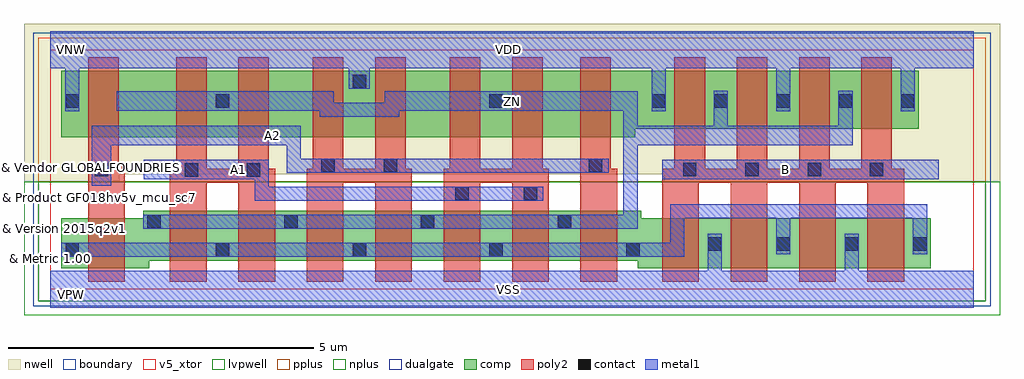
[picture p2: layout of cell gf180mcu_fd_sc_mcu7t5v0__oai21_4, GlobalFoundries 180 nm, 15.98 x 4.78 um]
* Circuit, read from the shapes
.subckt gf180mcu_fd_sc_mcu7t5v0__oai21_4 A1 A2 B VDD VNW VSS ZN
XM1 ZN A2 n1 VSUBS nfet_05v0 w=0.82u l=0.6u m=4
XM2 n1 A1 ZN VSUBS nfet_05v0 w=0.82u l=0.6u m=4
XM3 VSS B n1 VSUBS nfet_05v0 w=0.82u l=0.6u m=4
XM4 n2 A2 VDD VNW pfet_05v0 w=1.095u l=0.5u
XM5 ZN A1 n2 VNW pfet_05v0 w=1.095u l=0.5u
XM6 n3 A1 ZN VNW pfet_05v0 w=1.095u l=0.5u
XM7 VDD A2 n3 VNW pfet_05v0 w=1.095u l=0.5u
XM8 n4 A2 VDD VNW pfet_05v0 w=1.095u l=0.5u
XM9 ZN A1 n4 VNW pfet_05v0 w=1.095u l=0.5u
XM10 n5 A1 ZN VNW pfet_05v0 w=1.095u l=0.5u
XM11 VDD A2 n5 VNW pfet_05v0 w=1.095u l=0.5u
XM12 ZN B VDD VNW pfet_05v0 w=0.955u l=0.5u m=4
.ends

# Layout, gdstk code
import gdstk
lib = gdstk.Library(unit=1e-6, precision=1e-09)
def R(c, l, rs):  # rectangles x0, y0, x1, y1
    for r in rs: c.add(gdstk.rectangle(r[:2], r[2:], *l))
def A(c, l, x, y, w, h, nx, ny, dx, dy):  # array of equal rectangles
    R(c, l, [(x+i*dx, y+j*dy, x+i*dx+w, y+j*dy+h) for i in range(nx) for j in range(ny)])
def P(c, l, *ps):  # polygons
    for p in ps: c.add(gdstk.Polygon(p, *l))
boundary = (0, 0)
nwell = (21, 0)
comp = (22, 0)
poly2 = (30, 0)
pplus = (31, 0)
nplus = (32, 0)
contact = (33, 0)
metal1 = (34, 0)
dualgate = (55, 0)
v5_xtor = (112, 1)
lvpwell = (204, 0)

gf180mcu_fd_sc_mcu7t5v0_ = lib.new_cell('gf180mcu_fd_sc_mcu7t5v0__oai21_4')
R(gf180mcu_fd_sc_mcu7t5v0_, boundary, [(0,0,15.12,3.92)])
P(gf180mcu_fd_sc_mcu7t5v0_, nwell, [(-0.43,1.76),(-0.43,4.35),(15.55,4.35),(15.55,1.76),(10.055,1.76),(10.055,1.885),(1.14,1.885),(1.14,1.76)])
P(gf180mcu_fd_sc_mcu7t5v0_, comp, [(0.18,2.485),(0.18,3.58),(14.22,3.58),(14.22,2.625),(9.58,2.625),(9.58,2.485)],
  [(0.18,0.34),(0.18,1.16),(1.52,1.16),(1.52,1.285),(9.68,1.285),(9.68,1.16),(14.42,1.16),(14.42,0.34),(9.62,0.34),(9.62,0.465),(1.62,0.465),(1.62,0.34)])
P(gf180mcu_fd_sc_mcu7t5v0_, poly2, [(0.62,0.12),(0.62,3.8),(1.12,3.8),(1.12,2.04),(1.22,2.04),(1.22,0.12)],
  [(1.96,0.12),(1.96,1.97),(2.06,1.97),(2.06,3.8),(2.56,3.8),(2.56,1.97),(3.08,1.97),(3.08,3.8),(3.58,3.8),(3.58,1.97),(3.68,1.97),(3.68,0.12),(3.08,0.12),(3.08,1.74),(2.56,1.74),(2.56,0.12)],
  [(4.2,0.12),(4.2,1.97),(4.3,1.97),(4.3,3.8),(4.8,3.8),(4.8,1.97),(5.32,1.97),(5.32,3.8),(5.82,3.8),(5.82,1.97),(5.92,1.97),(5.92,0.12),(5.32,0.12),(5.32,1.74),(4.8,1.74),(4.8,0.12)],
  [(6.44,0.12),(6.44,1.97),(6.54,1.97),(6.54,3.8),(7.04,3.8),(7.04,1.97),(7.56,1.97),(7.56,3.8),(8.06,3.8),(8.06,1.97),(8.16,1.97),(8.16,0.12),(7.56,0.12),(7.56,1.74),(7.04,1.74),(7.04,0.12)],
  [(8.68,0.12),(8.68,3.8),(9.18,3.8),(9.18,1.97),(9.28,1.97),(9.28,0.12)],
  [(10.02,0.12),(10.02,1.97),(10.22,1.97),(10.22,3.8),(10.72,3.8),(10.72,1.97),(11.24,1.97),(11.24,3.8),(11.74,3.8),(11.74,1.97),(12.26,1.97),(12.26,3.8),(12.76,3.8),(12.76,1.97),(13.28,1.97),(13.28,3.8),(13.78,3.8),(13.78,1.97),(13.98,1.97),(13.98,0.12),(13.38,0.12),(13.38,1.74),(12.86,1.74),(12.86,0.12),(12.26,0.12),(12.26,1.74),(11.74,1.74),(11.74,0.12),(11.14,0.12),(11.14,1.74),(10.62,1.74),(10.62,0.12)])
R(gf180mcu_fd_sc_mcu7t5v0_, pplus, [(-0.2,1.76,15.32,4.12)])
R(gf180mcu_fd_sc_mcu7t5v0_, nplus, [(-0.2,-0.2,15.32,1.76)])
A(gf180mcu_fd_sc_mcu7t5v0_, contact, 2.71, 0.535, 0.22, 0.22, 4, 1, 2.24, 0)
A(gf180mcu_fd_sc_mcu7t5v0_, contact, 10.77, 0.63, 0.22, 0.22, 4, 1, 1.12, 0)
A(gf180mcu_fd_sc_mcu7t5v0_, contact, 1.59, 0.995, 0.22, 0.22, 4, 1, 2.24, 0)
A(gf180mcu_fd_sc_mcu7t5v0_, contact, 10.36, 1.85, 0.22, 0.22, 4, 1, 1.02, 0)
A(gf180mcu_fd_sc_mcu7t5v0_, contact, 9.85, 2.97, 0.22, 0.22, 5, 1, 1.02, 0)
R(gf180mcu_fd_sc_mcu7t5v0_, contact, [(0.25,0.535,0.47,0.755), (6.63,1.455,6.85,1.675), (7.75,1.455,7.97,1.675), (2.2,1.845,2.42,2.065), (3.22,1.845,3.44,2.065), (0.73,1.85,0.95,2.07), (4.44,1.915,4.66,2.135), (5.46,1.915,5.68,2.135), (8.82,1.915,9.04,2.135), (0.25,2.97,0.47,3.19), (2.71,2.97,2.93,3.19), (7.19,2.97,7.41,3.19), (4.95,3.29,5.17,3.51)])
R(gf180mcu_fd_sc_mcu7t5v0_, metal1, [(10.02,1.8,14.55,2.12)])
P(gf180mcu_fd_sc_mcu7t5v0_, metal1, [(3.35,1.45),(3.35,1.8),(1.53,1.8),(1.53,2.12),(3.58,2.12),(3.58,1.68),(8.07,1.68),(8.07,1.45)],
  [(0.68,1.695),(0.68,2.68),(4.1,2.68),(4.1,2.14),(9.14,2.14),(9.14,1.91),(3.87,1.91),(3.87,2.36),(1,2.36),(1,1.695)],
  [(1.52,0.99),(1.52,1.22),(9.385,1.22),(9.385,2.92),(5.71,2.92),(5.71,2.825),(4.41,2.825),(4.41,2.92),(1.085,2.92),(1.085,3.24),(4.64,3.24),(4.64,3.055),(5.48,3.055),(5.48,3.24),(9.615,3.24),(9.615,2.68),(10.865,2.68),(10.865,3.25),(11.095,3.25),(11.095,2.68),(12.905,2.68),(12.905,3.25),(13.135,3.25),(13.135,2.36),(9.615,2.36),(9.615,0.99)],
  [(0.18,0.53),(0.18,0.76),(10.15,0.76),(10.15,1.39),(14.355,1.39),(14.355,0.57),(14.125,0.57),(14.125,1.16),(12.115,1.16),(12.115,0.57),(11.885,0.57),(11.885,1.16),(10.38,1.16),(10.38,0.53)],
  [(0,-0.3),(0,0.3),(10.765,0.3),(10.765,0.91),(10.995,0.91),(10.995,0.3),(13.005,0.3),(13.005,0.91),(13.235,0.91),(13.235,0.3),(15.12,0.3),(15.12,-0.3)],
  [(0.245,2.91),(0.245,3.62),(0,3.62),(0,4.22),(15.12,4.22),(15.12,3.62),(14.155,3.62),(14.155,2.91),(13.925,2.91),(13.925,3.62),(12.115,3.62),(12.115,2.91),(11.885,2.91),(11.885,3.62),(10.075,3.62),(10.075,2.91),(9.845,2.91),(9.845,3.62),(5.23,3.62),(5.23,3.285),(4.89,3.285),(4.89,3.62),(0.475,3.62),(0.475,2.91)])
R(gf180mcu_fd_sc_mcu7t5v0_, dualgate, [(-0.28,-0.28,15.4,4.2)])
R(gf180mcu_fd_sc_mcu7t5v0_, v5_xtor, [(0,0,15.12,3.92)])
R(gf180mcu_fd_sc_mcu7t5v0_, lvpwell, [(-0.43,-0.43,15.55,1.76)])
gf180mcu_fd_sc_mcu7t5v0_.add(gdstk.Label('B', (12.04,1.96), layer=34, texttype=10))
gf180mcu_fd_sc_mcu7t5v0_.add(gdstk.Label('VDD', (7.5,3.92), layer=34, texttype=10))
gf180mcu_fd_sc_mcu7t5v0_.add(gdstk.Label('VSS', (7.5,0), layer=34, texttype=10))
gf180mcu_fd_sc_mcu7t5v0_.add(gdstk.Label('A1', (3.08,1.96), layer=34, texttype=10))
gf180mcu_fd_sc_mcu7t5v0_.add(gdstk.Label('ZN', (7.56,3.08), layer=34, texttype=10))
gf180mcu_fd_sc_mcu7t5v0_.add(gdstk.Label('A2', (3.64,2.52), layer=34, texttype=10))
gf180mcu_fd_sc_mcu7t5v0_.add(gdstk.Label('& Vendor GLOBALFOUNDRIES', (0,2), layer=63, texttype=63))
gf180mcu_fd_sc_mcu7t5v0_.add(gdstk.Label('& Product GF018hv5v_mcu_sc7', (0,1.5), layer=63, texttype=63))
gf180mcu_fd_sc_mcu7t5v0_.add(gdstk.Label('& Version 2015q2v1', (0,1), layer=63, texttype=63))
gf180mcu_fd_sc_mcu7t5v0_.add(gdstk.Label('& Metric 1.00', (0,0.5), layer=63, texttype=63))
gf180mcu_fd_sc_mcu7t5v0_.add(gdstk.Label('VNW', (0.345,3.92), layer=21, texttype=10))
gf180mcu_fd_sc_mcu7t5v0_.add(gdstk.Label('VPW', (0.34,-0.085), layer=204, texttype=10))

lib.write_gds('gf180mcu_fd_sc_mcu7t5v0__oai21_4.gds')
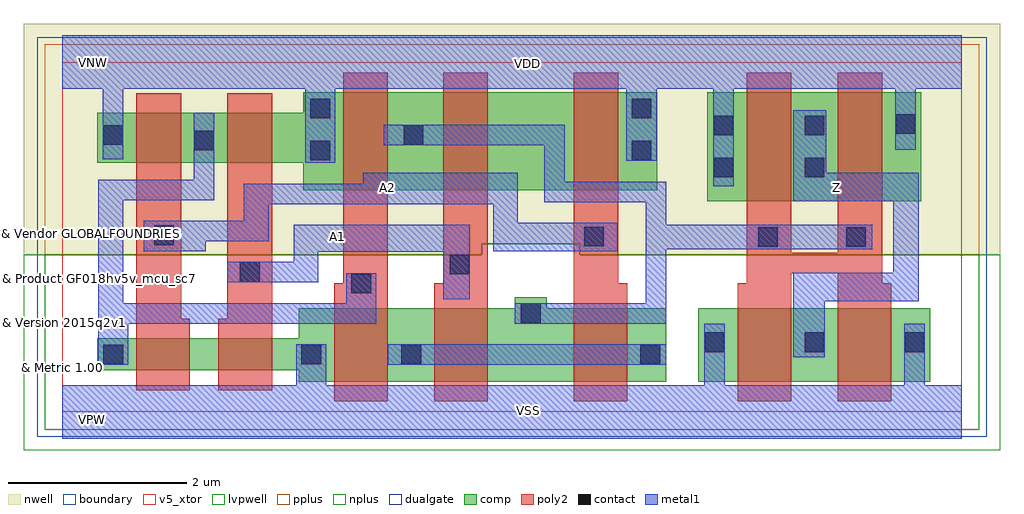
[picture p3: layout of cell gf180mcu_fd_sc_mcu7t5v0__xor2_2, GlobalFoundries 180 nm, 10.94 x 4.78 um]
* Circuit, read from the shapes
.subckt gf180mcu_fd_sc_mcu7t5v0__xor2_2 A1 A2 VDD VNW VSS Z
XM1 n1 A2 n2 VSUBS nfet_05v0 w=0.36u l=0.6u
XM2 VSS A1 n1 VSUBS nfet_05v0 w=0.36u l=0.6u
XM3 n3 n2 VSS VSUBS nfet_05v0 w=0.82u l=0.6u
XM4 n4 A1 n3 VSUBS nfet_05v0 w=0.82u l=0.6u
XM5 n3 A2 n4 VSUBS nfet_05v0 w=0.82u l=0.6u
XM6 Z n4 VSS VSUBS nfet_05v0 w=0.82u l=0.6u m=2
XM7 n2 A2 VDD VNW pfet_05v0 w=0.56u l=0.5u
XM8 VDD A1 n2 VNW pfet_05v0 w=0.56u l=0.5u
XM9 n4 n2 VDD VNW pfet_05v0 w=1.095u l=0.5u
XM10 n5 A1 n4 VNW pfet_05v0 w=1.095u l=0.5u
XM11 VDD A2 n5 VNW pfet_05v0 w=1.095u l=0.5u
XM12 Z n4 VDD VNW pfet_05v0 w=1.22u l=0.5u m=2
.ends

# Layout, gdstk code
import gdstk
lib = gdstk.Library(unit=1e-6, precision=1e-09)
def R(c, l, rs):  # rectangles x0, y0, x1, y1
    for r in rs: c.add(gdstk.rectangle(r[:2], r[2:], *l))
def A(c, l, x, y, w, h, nx, ny, dx, dy):  # array of equal rectangles
    R(c, l, [(x+i*dx, y+j*dy, x+i*dx+w, y+j*dy+h) for i in range(nx) for j in range(ny)])
def P(c, l, *ps):  # polygons
    for p in ps: c.add(gdstk.Polygon(p, *l))
boundary = (0, 0)
nwell = (21, 0)
comp = (22, 0)
poly2 = (30, 0)
pplus = (31, 0)
nplus = (32, 0)
contact = (33, 0)
metal1 = (34, 0)
dualgate = (55, 0)
v5_xtor = (112, 1)
lvpwell = (204, 0)

gf180mcu_fd_sc_mcu7t5v0_ = lib.new_cell('gf180mcu_fd_sc_mcu7t5v0__xor2_2')
R(gf180mcu_fd_sc_mcu7t5v0_, boundary, [(0,0,10.08,3.92)])
P(gf180mcu_fd_sc_mcu7t5v0_, nwell, [(-0.43,1.76),(-0.43,4.35),(10.51,4.35),(10.51,1.76),(5.8,1.76),(5.8,1.885),(4.7,1.885),(4.7,1.76)])
R(gf180mcu_fd_sc_mcu7t5v0_, comp, [(7.13,0.34,9.73,1.16), (7.23,2.36,9.63,3.58)])
P(gf180mcu_fd_sc_mcu7t5v0_, comp, [(2.7,2.485),(2.7,2.79),(0.39,2.79),(0.39,3.35),(2.7,3.35),(2.7,3.58),(6.67,3.58),(6.67,2.485)],
  [(2.65,0.34),(2.65,0.465),(0.39,0.465),(0.39,0.825),(2.65,0.825),(2.65,1.16),(5.07,1.16),(5.07,1.285),(5.43,1.285),(5.43,1.16),(6.77,1.16),(6.77,0.34)])
P(gf180mcu_fd_sc_mcu7t5v0_, poly2, [(0.83,0.245),(0.83,3.57),(1.33,3.57),(1.33,1.045),(1.43,1.045),(1.43,0.245)],
  [(1.75,0.245),(1.75,1.045),(1.85,1.045),(1.85,3.57),(2.35,3.57),(2.35,0.245)],
  [(3.05,0.12),(3.05,1.44),(3.15,1.44),(3.15,3.8),(3.65,3.8),(3.65,0.12)],
  [(4.17,0.12),(4.17,1.44),(4.27,1.44),(4.27,3.8),(4.77,3.8),(4.77,0.12)],
  [(5.73,0.12),(5.73,3.8),(6.23,3.8),(6.23,1.44),(6.33,1.44),(6.33,0.12)],
  [(7.57,0.12),(7.57,1.44),(7.67,1.44),(7.67,3.8),(8.17,3.8),(8.17,1.785),(8.69,1.785),(8.69,3.8),(9.19,3.8),(9.19,1.44),(9.29,1.44),(9.29,0.12),(8.69,0.12),(8.69,1.555),(8.17,1.555),(8.17,0.12)])
P(gf180mcu_fd_sc_mcu7t5v0_, pplus, [(-0.2,1.76),(-0.2,4.12),(10.28,4.12),(10.28,1.76),(5.8,1.76),(5.8,1.885),(4.7,1.885),(4.7,1.76)])
P(gf180mcu_fd_sc_mcu7t5v0_, nplus, [(-0.2,-0.2),(-0.2,1.76),(4.7,1.76),(4.7,1.885),(5.8,1.885),(5.8,1.76),(10.28,1.76),(10.28,-0.2)])
A(gf180mcu_fd_sc_mcu7t5v0_, contact, 7.2, 0.67, 0.22, 0.22, 3, 1, 1.12, 0)
R(gf180mcu_fd_sc_mcu7t5v0_, contact, [(0.46,0.535,0.68,0.755), (2.68,0.535,2.9,0.755), (3.8,0.535,4.02,0.755), (6.48,0.535,6.7,0.755), (5.14,0.995,5.36,1.215), (3.24,1.33,3.46,1.55), (1.99,1.455,2.21,1.675), (4.34,1.54,4.56,1.76), (7.8,1.85,8.02,2.07), (8.785,1.85,9.005,2.07), (5.85,1.855,6.07,2.075), (1.03,1.87,1.25,2.09), (7.3,2.63,7.52,2.85), (8.32,2.63,8.54,2.85), (2.78,2.82,3,3.04), (6.38,2.82,6.6,3.04), (1.48,2.93,1.7,3.15), (0.46,2.995,0.68,3.215), (3.825,2.995,4.045,3.215), (7.3,3.1,7.52,3.32), (8.32,3.1,8.54,3.32), (9.34,3.115,9.56,3.335), (2.78,3.29,3,3.51), (6.38,3.29,6.6,3.51)])
R(gf180mcu_fd_sc_mcu7t5v0_, metal1, [(3.65,0.53,6.77,0.76)])
P(gf180mcu_fd_sc_mcu7t5v0_, metal1, [(0.4,0.53),(0.4,2.6),(1.475,2.6),(1.475,3.35),(1.705,3.35),(1.705,2.37),(0.68,2.37),(0.68,1.22),(3.18,1.22),(3.18,1.555),(3.52,1.555),(3.52,0.99),(0.74,0.99),(0.74,0.53)],
  [(4.27,1.265),(4.27,1.795),(2.87,1.795),(2.87,1.45),(1.85,1.45),(1.85,1.68),(2.595,1.68),(2.595,2.095),(4.565,2.095),(4.565,1.265)],
  [(0.915,1.8),(0.915,2.14),(2.035,2.14),(2.035,2.555),(3.375,2.555),(3.375,2.68),(5.105,2.68),(5.105,2.12),(6.225,2.12),(6.225,1.8),(4.83,1.8),(4.83,2.325),(2.315,2.325),(2.315,1.91),(1.61,1.91),(1.61,1.8)],
  [(5.07,0.99),(5.07,1.22),(6.54,1.22),(6.54,2.35),(5.4,2.35),(5.4,2.99),(3.6,2.99),(3.6,3.22),(5.63,3.22),(5.63,2.58),(6.77,2.58),(6.77,2.095),(9.08,2.095),(9.08,1.82),(6.77,1.82),(6.77,0.99)],
  [(8.195,0.61),(8.195,1.56),(9.315,1.56),(9.315,2.36),(8.195,2.36),(8.195,3.38),(8.56,3.38),(8.56,2.68),(9.6,2.68),(9.6,1.24),(8.545,1.24),(8.545,0.61)],
  [(0,-0.3),(0,0.3),(2.62,0.3),(2.62,0.76),(2.96,0.76),(2.96,0.3),(7.195,0.3),(7.195,0.99),(7.425,0.99),(7.425,0.3),(9.435,0.3),(9.435,0.99),(9.665,0.99),(9.665,0.3),(10.08,0.3),(10.08,-0.3)],
  [(7.295,2.53),(7.295,3.62),(6.66,3.62),(6.66,2.815),(6.32,2.815),(6.32,3.62),(3.06,3.62),(3.06,2.79),(2.72,2.79),(2.72,3.62),(0.685,3.62),(0.685,2.83),(0.455,2.83),(0.455,3.62),(0,3.62),(0,4.22),(10.08,4.22),(10.08,3.62),(9.565,3.62),(9.565,2.94),(9.335,2.94),(9.335,3.62),(7.525,3.62),(7.525,2.53)])
R(gf180mcu_fd_sc_mcu7t5v0_, dualgate, [(-0.28,-0.28,10.36,4.2)])
R(gf180mcu_fd_sc_mcu7t5v0_, v5_xtor, [(0,0,10.08,3.92)])
P(gf180mcu_fd_sc_mcu7t5v0_, lvpwell, [(-0.43,-0.43),(-0.43,1.76),(4.7,1.76),(4.7,1.885),(5.8,1.885),(5.8,1.76),(10.51,1.76),(10.51,-0.43)])
gf180mcu_fd_sc_mcu7t5v0_.add(gdstk.Label('VDD', (5.215,3.905), layer=34, texttype=10))
gf180mcu_fd_sc_mcu7t5v0_.add(gdstk.Label('VSS', (5.23,0.015), layer=34, texttype=10))
gf180mcu_fd_sc_mcu7t5v0_.add(gdstk.Label('Z', (8.68,2.52), layer=34, texttype=10))
gf180mcu_fd_sc_mcu7t5v0_.add(gdstk.Label('A1', (3.08,1.96), layer=34, texttype=10))
gf180mcu_fd_sc_mcu7t5v0_.add(gdstk.Label('A2', (3.64,2.52), layer=34, texttype=10))
gf180mcu_fd_sc_mcu7t5v0_.add(gdstk.Label('& Vendor GLOBALFOUNDRIES', (0,2), layer=63, texttype=63))
gf180mcu_fd_sc_mcu7t5v0_.add(gdstk.Label('& Product GF018hv5v_mcu_sc7', (0,1.5), layer=63, texttype=63))
gf180mcu_fd_sc_mcu7t5v0_.add(gdstk.Label('& Version 2015q2v1', (0,1), layer=63, texttype=63))
gf180mcu_fd_sc_mcu7t5v0_.add(gdstk.Label('& Metric 1.00', (0,0.5), layer=63, texttype=63))
gf180mcu_fd_sc_mcu7t5v0_.add(gdstk.Label('VNW', (0.345,3.92), layer=21, texttype=10))
gf180mcu_fd_sc_mcu7t5v0_.add(gdstk.Label('VPW', (0.34,-0.085), layer=204, texttype=10))

lib.write_gds('gf180mcu_fd_sc_mcu7t5v0__xor2_2.gds')
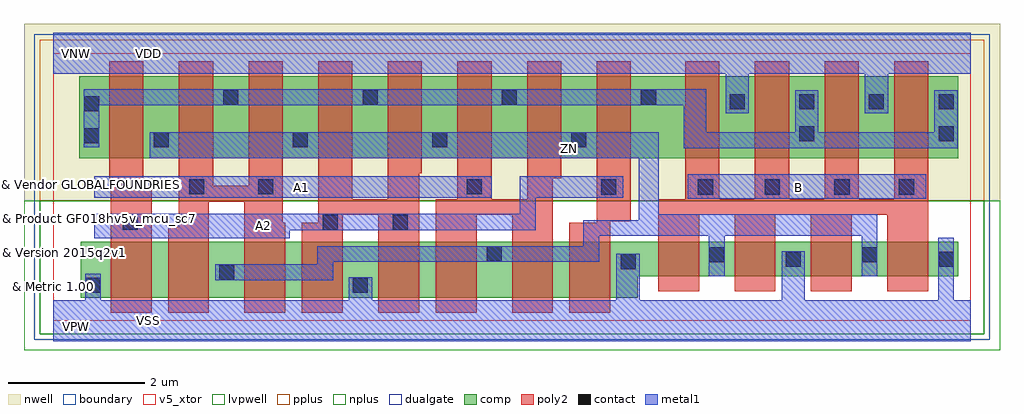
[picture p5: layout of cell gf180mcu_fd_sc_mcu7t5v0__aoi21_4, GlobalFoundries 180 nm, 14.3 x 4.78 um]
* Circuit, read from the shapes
.subckt gf180mcu_fd_sc_mcu7t5v0__aoi21_4 A1 A2 B VDD VNW VSS ZN
XM1 n1 A2 VSS VSUBS nfet_05v0 w=0.82u l=0.6u
XM2 ZN A1 n1 VSUBS nfet_05v0 w=0.82u l=0.6u
XM3 n2 A1 ZN VSUBS nfet_05v0 w=0.82u l=0.6u
XM4 VSS A2 n2 VSUBS nfet_05v0 w=0.82u l=0.6u
XM5 n3 A2 VSS VSUBS nfet_05v0 w=0.82u l=0.6u
XM6 ZN A1 n3 VSUBS nfet_05v0 w=0.82u l=0.6u
XM7 n4 A1 ZN VSUBS nfet_05v0 w=0.82u l=0.6u
XM8 VSS A2 n4 VSUBS nfet_05v0 w=0.82u l=0.6u
XM9 ZN B VSS VSUBS nfet_05v0 w=0.51u l=0.6u m=4
XM10 ZN A2 n5 VNW pfet_05v0 w=1.2u l=0.5u m=4
XM11 n5 A1 ZN VNW pfet_05v0 w=1.2u l=0.5u m=4
XM12 VDD B n5 VNW pfet_05v0 w=1.2u l=0.5u m=4
.ends

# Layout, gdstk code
import gdstk
lib = gdstk.Library(unit=1e-6, precision=1e-09)
def R(c, l, rs):  # rectangles x0, y0, x1, y1
    for r in rs: c.add(gdstk.rectangle(r[:2], r[2:], *l))
def A(c, l, x, y, w, h, nx, ny, dx, dy):  # array of equal rectangles
    R(c, l, [(x+i*dx, y+j*dy, x+i*dx+w, y+j*dy+h) for i in range(nx) for j in range(ny)])
def P(c, l, *ps):  # polygons
    for p in ps: c.add(gdstk.Polygon(p, *l))
boundary = (0, 0)
nwell = (21, 0)
comp = (22, 0)
poly2 = (30, 0)
pplus = (31, 0)
nplus = (32, 0)
contact = (33, 0)
metal1 = (34, 0)
dualgate = (55, 0)
v5_xtor = (112, 1)
lvpwell = (204, 0)

gf180mcu_fd_sc_mcu7t5v0_ = lib.new_cell('gf180mcu_fd_sc_mcu7t5v0__aoi21_4')
R(gf180mcu_fd_sc_mcu7t5v0_, boundary, [(0,0,13.44,3.92)])
R(gf180mcu_fd_sc_mcu7t5v0_, nwell, [(-0.43,1.76,13.87,4.35)])
R(gf180mcu_fd_sc_mcu7t5v0_, comp, [(0.38,2.38,13.26,3.58)])
P(gf180mcu_fd_sc_mcu7t5v0_, comp, [(0.4,0.34),(0.4,1.16),(13.26,1.16),(13.26,0.65),(8.56,0.65),(8.56,0.34)])
P(gf180mcu_fd_sc_mcu7t5v0_, poly2, [(0.84,0.12),(0.84,2.085),(0.82,2.085),(0.82,3.8),(1.32,3.8),(1.32,2.08),(1.44,2.08),(1.44,0.12)],
  [(1.68,0.12),(1.68,1.38),(1.84,1.38),(1.84,3.8),(2.34,3.8),(2.34,1.975),(2.86,1.975),(2.86,3.8),(3.36,3.8),(3.36,1.435),(3.4,1.435),(3.4,0.12),(2.8,0.12),(2.8,1.745),(2.28,1.745),(2.28,0.12)],
  [(3.64,0.12),(3.64,1.435),(3.88,1.435),(3.88,3.8),(4.38,3.8),(4.38,1.78),(4.9,1.78),(4.9,3.8),(5.4,3.8),(5.4,2.16),(5.36,2.16),(5.36,0.12),(4.76,0.12),(4.76,1.55),(4.24,1.55),(4.24,0.12)],
  [(5.6,0.12),(5.6,1.78),(5.92,1.78),(5.92,3.8),(6.42,3.8),(6.42,1.78),(6.94,1.78),(6.94,3.8),(7.44,3.8),(7.44,2.085),(7.32,2.085),(7.32,0.12),(6.72,0.12),(6.72,1.55),(6.2,1.55),(6.2,0.12)],
  [(7.56,0.12),(7.56,1.435),(7.96,1.435),(7.96,3.8),(8.46,3.8),(8.46,1.46),(8.16,1.46),(8.16,0.12)],
  [(8.86,0.43),(8.86,1.78),(9.26,1.78),(9.26,3.8),(9.76,3.8),(9.76,1.78),(10.28,1.78),(10.28,3.8),(10.78,3.8),(10.78,1.78),(11.3,1.78),(11.3,3.8),(11.8,3.8),(11.8,1.78),(12.32,1.78),(12.32,3.8),(12.82,3.8),(12.82,0.43),(12.22,0.43),(12.22,1.55),(11.7,1.55),(11.7,0.43),(11.1,0.43),(11.1,1.55),(10.58,1.55),(10.58,0.43),(9.98,0.43),(9.98,1.55),(9.46,1.55),(9.46,0.43)])
R(gf180mcu_fd_sc_mcu7t5v0_, pplus, [(-0.2,1.76,13.64,4.12)])
R(gf180mcu_fd_sc_mcu7t5v0_, nplus, [(-0.2,-0.2,13.64,1.76)])
A(gf180mcu_fd_sc_mcu7t5v0_, contact, 1.47, 2.54, 0.22, 0.22, 4, 1, 2.04, 0)
A(gf180mcu_fd_sc_mcu7t5v0_, contact, 9.91, 3.1, 0.22, 0.22, 4, 1, 1.02, 0)
A(gf180mcu_fd_sc_mcu7t5v0_, contact, 2.49, 3.165, 0.22, 0.22, 4, 1, 2.04, 0)
R(gf180mcu_fd_sc_mcu7t5v0_, contact, [(0.47,0.41,0.69,0.63), (4.39,0.41,4.61,0.63), (2.43,0.6,2.65,0.82), (8.31,0.755,8.53,0.975), (10.73,0.79,10.95,1.01), (12.97,0.79,13.19,1.01), (9.61,0.86,9.83,1.08), (11.85,0.86,12.07,1.08), (6.35,0.87,6.57,1.09), (1.015,1.335,1.235,1.555), (3.95,1.335,4.17,1.555), (4.97,1.335,5.19,1.555), (8.03,1.85,8.25,2.07), (9.445,1.85,9.665,2.07), (10.425,1.85,10.645,2.07), (11.445,1.85,11.665,2.07), (12.39,1.85,12.61,2.07), (1.99,1.855,2.21,2.075), (3.005,1.855,3.225,2.075), (6.06,1.855,6.28,2.075), (0.45,2.6,0.67,2.82), (10.93,2.63,11.15,2.85), (12.97,2.63,13.19,2.85), (0.45,3.07,0.67,3.29)])
R(gf180mcu_fd_sc_mcu7t5v0_, metal1, [(9.295,1.79,12.79,2.15), (0.6,1.8,6.42,2.12)])
P(gf180mcu_fd_sc_mcu7t5v0_, metal1, [(0.6,1.21),(0.6,1.57),(6.835,1.57),(6.835,2.12),(8.35,2.12),(8.35,1.805),(7.065,1.805),(7.065,1.325),(3.465,1.325),(3.465,1.21)],
  [(2.37,0.595),(2.37,0.825),(3.87,0.825),(3.87,1.095),(7.765,1.095),(7.765,1.475),(8.58,1.475),(8.58,2.38),(1.41,2.38),(1.41,2.765),(8.87,2.765),(8.87,1.56),(12.075,1.56),(12.075,0.655),(11.845,0.655),(11.845,1.245),(9.835,1.245),(9.835,0.655),(9.605,0.655),(9.605,1.245),(7.995,1.245),(7.995,0.865),(4.1,0.865),(4.1,0.595)],
  [(9.235,2.53),(9.235,3.16),(0.675,3.16),(0.675,2.54),(0.445,2.54),(0.445,3.39),(9.565,3.39),(9.565,2.76),(10.87,2.76),(10.87,3.38),(11.21,3.38),(11.21,2.76),(12.91,2.76),(12.91,3.38),(13.25,3.38),(13.25,2.53)],
  [(0,-0.3),(0,0.3),(0.465,0.3),(0.465,0.69),(0.695,0.69),(0.695,0.3),(4.33,0.3),(4.33,0.635),(4.67,0.635),(4.67,0.3),(8.25,0.3),(8.25,0.98),(8.59,0.98),(8.59,0.3),(10.67,0.3),(10.67,1.015),(11.01,1.015),(11.01,0.3),(12.965,0.3),(12.965,1.215),(13.195,1.215),(13.195,0.3),(13.44,0.3),(13.44,-0.3)],
  [(9.85,3.04),(9.85,3.62),(0,3.62),(0,4.22),(13.44,4.22),(13.44,3.62),(12.23,3.62),(12.23,3.04),(11.89,3.04),(11.89,3.62),(10.19,3.62),(10.19,3.04)])
R(gf180mcu_fd_sc_mcu7t5v0_, dualgate, [(-0.28,-0.28,13.72,4.2)])
R(gf180mcu_fd_sc_mcu7t5v0_, v5_xtor, [(0,0,13.44,3.92)])
R(gf180mcu_fd_sc_mcu7t5v0_, lvpwell, [(-0.43,-0.43,13.87,1.76)])
gf180mcu_fd_sc_mcu7t5v0_.add(gdstk.Label('A2', (3.08,1.4), layer=34, texttype=10))
gf180mcu_fd_sc_mcu7t5v0_.add(gdstk.Label('B', (10.92,1.96), layer=34, texttype=10))
gf180mcu_fd_sc_mcu7t5v0_.add(gdstk.Label('VDD', (1.4,3.92), layer=34, texttype=10))
gf180mcu_fd_sc_mcu7t5v0_.add(gdstk.Label('VSS', (1.4,0), layer=34, texttype=10))
gf180mcu_fd_sc_mcu7t5v0_.add(gdstk.Label('ZN', (7.56,2.52), layer=34, texttype=10))
gf180mcu_fd_sc_mcu7t5v0_.add(gdstk.Label('A1', (3.64,1.96), layer=34, texttype=10))
gf180mcu_fd_sc_mcu7t5v0_.add(gdstk.Label('& Vendor GLOBALFOUNDRIES', (0,2), layer=63, texttype=63))
gf180mcu_fd_sc_mcu7t5v0_.add(gdstk.Label('& Product GF018hv5v_mcu_sc7', (0,1.5), layer=63, texttype=63))
gf180mcu_fd_sc_mcu7t5v0_.add(gdstk.Label('& Version 2015q2v1', (0,1), layer=63, texttype=63))
gf180mcu_fd_sc_mcu7t5v0_.add(gdstk.Label('& Metric 1.00', (0,0.5), layer=63, texttype=63))
gf180mcu_fd_sc_mcu7t5v0_.add(gdstk.Label('VNW', (0.345,3.92), layer=21, texttype=10))
gf180mcu_fd_sc_mcu7t5v0_.add(gdstk.Label('VPW', (0.34,-0.085), layer=204, texttype=10))

lib.write_gds('gf180mcu_fd_sc_mcu7t5v0__aoi21_4.gds')
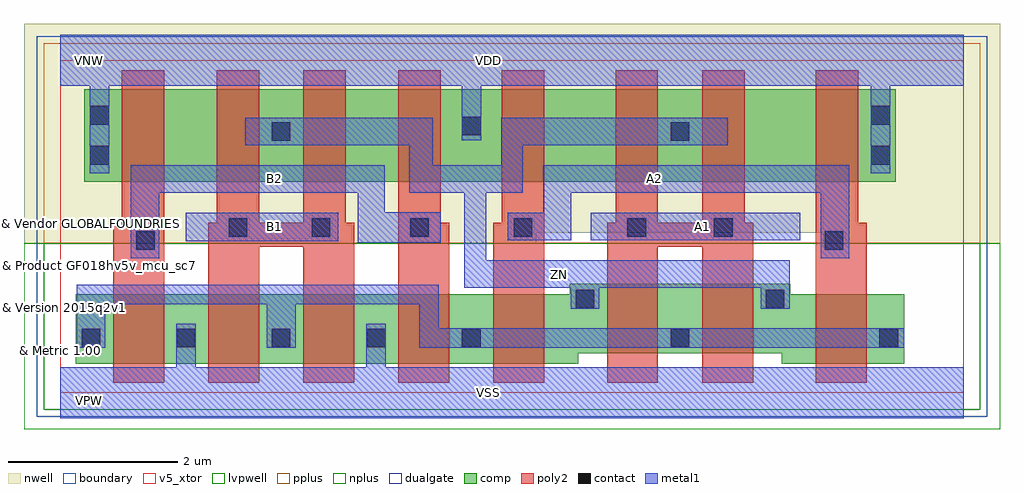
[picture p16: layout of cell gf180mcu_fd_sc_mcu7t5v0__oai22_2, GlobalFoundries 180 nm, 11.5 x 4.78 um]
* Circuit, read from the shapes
.subckt gf180mcu_fd_sc_mcu7t5v0__oai22_2 A1 A2 B1 B2 VDD VNW VSS ZN
XM1 VSS B2 n1 VSUBS nfet_05v0 w=0.82u l=0.6u m=2
XM2 n1 B1 VSS VSUBS nfet_05v0 w=0.82u l=0.6u m=2
XM3 ZN A2 n1 VSUBS nfet_05v0 w=0.82u l=0.6u m=2
XM4 n1 A1 ZN VSUBS nfet_05v0 w=0.82u l=0.6u m=2
XM5 n2 B2 VDD VNW pfet_05v0 w=1.095u l=0.5u
XM6 ZN B1 n2 VNW pfet_05v0 w=1.095u l=0.5u
XM7 n3 B1 ZN VNW pfet_05v0 w=1.095u l=0.5u
XM8 VDD B2 n3 VNW pfet_05v0 w=1.095u l=0.5u
XM9 n4 A2 VDD VNW pfet_05v0 w=1.095u l=0.5u
XM10 ZN A1 n4 VNW pfet_05v0 w=1.095u l=0.5u
XM11 n5 A1 ZN VNW pfet_05v0 w=1.095u l=0.5u
XM12 VDD A2 n5 VNW pfet_05v0 w=1.095u l=0.5u
.ends

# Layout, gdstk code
import gdstk
lib = gdstk.Library(unit=1e-6, precision=1e-09)
def R(c, l, rs):  # rectangles x0, y0, x1, y1
    for r in rs: c.add(gdstk.rectangle(r[:2], r[2:], *l))
def A(c, l, x, y, w, h, nx, ny, dx, dy):  # array of equal rectangles
    R(c, l, [(x+i*dx, y+j*dy, x+i*dx+w, y+j*dy+h) for i in range(nx) for j in range(ny)])
def P(c, l, *ps):  # polygons
    for p in ps: c.add(gdstk.Polygon(p, *l))
boundary = (0, 0)
nwell = (21, 0)
comp = (22, 0)
poly2 = (30, 0)
pplus = (31, 0)
nplus = (32, 0)
contact = (33, 0)
metal1 = (34, 0)
dualgate = (55, 0)
v5_xtor = (112, 1)
lvpwell = (204, 0)

gf180mcu_fd_sc_mcu7t5v0_ = lib.new_cell('gf180mcu_fd_sc_mcu7t5v0__oai22_2')
R(gf180mcu_fd_sc_mcu7t5v0_, boundary, [(0,0,10.64,3.92)])
P(gf180mcu_fd_sc_mcu7t5v0_, nwell, [(-0.43,1.76),(-0.43,4.35),(11.07,4.35),(11.07,1.76),(8.985,1.76),(8.985,1.885),(5.605,1.885),(5.605,1.76)])
R(gf180mcu_fd_sc_mcu7t5v0_, comp, [(0.28,2.485,9.84,3.58)])
P(gf180mcu_fd_sc_mcu7t5v0_, comp, [(0.18,0.34),(0.18,1.16),(6,1.16),(6,1.285),(8.6,1.285),(8.6,1.16),(9.94,1.16),(9.94,0.34),(8.5,0.34),(8.5,0.465),(6.1,0.465),(6.1,0.34)])
P(gf180mcu_fd_sc_mcu7t5v0_, poly2, [(0.62,0.12),(0.62,2.005),(0.72,2.005),(0.72,3.8),(1.22,3.8),(1.22,0.12)],
  [(1.74,0.12),(1.74,2.005),(1.84,2.005),(1.84,3.8),(2.34,3.8),(2.34,2.005),(2.86,2.005),(2.86,3.8),(3.36,3.8),(3.36,2.005),(3.46,2.005),(3.46,0.12),(2.86,0.12),(2.86,1.72),(2.34,1.72),(2.34,0.12)],
  [(3.98,0.12),(3.98,3.8),(4.48,3.8),(4.48,2.005),(4.58,2.005),(4.58,0.12)],
  [(5.1,0.12),(5.1,2.005),(5.2,2.005),(5.2,3.8),(5.7,3.8),(5.7,0.12)],
  [(6.44,0.12),(6.44,2.005),(6.54,2.005),(6.54,3.8),(7.04,3.8),(7.04,2.005),(7.56,2.005),(7.56,3.8),(8.06,3.8),(8.06,2.005),(8.16,2.005),(8.16,0.12),(7.56,0.12),(7.56,1.72),(7.04,1.72),(7.04,0.12)],
  [(8.9,0.12),(8.9,3.8),(9.4,3.8),(9.4,2.005),(9.5,2.005),(9.5,0.12)])
R(gf180mcu_fd_sc_mcu7t5v0_, pplus, [(-0.2,1.76,10.84,4.12)])
R(gf180mcu_fd_sc_mcu7t5v0_, nplus, [(-0.2,-0.2,10.84,1.76)])
A(gf180mcu_fd_sc_mcu7t5v0_, contact, 0.25, 0.535, 0.22, 0.22, 5, 1, 1.12, 0)
R(gf180mcu_fd_sc_mcu7t5v0_, contact, [(7.19,0.535,7.41,0.755), (9.65,0.535,9.87,0.755), (6.07,0.995,6.29,1.215), (8.31,0.995,8.53,1.215), (0.89,1.685,1.11,1.905), (9.005,1.685,9.225,1.905), (1.98,1.84,2.2,2.06), (2.96,1.84,3.18,2.06), (4.12,1.84,4.34,2.06), (5.34,1.84,5.56,2.06), (6.68,1.84,6.9,2.06), (7.7,1.84,7.92,2.06), (0.35,2.69,0.57,2.91), (9.55,2.69,9.77,2.91), (2.49,2.97,2.71,3.19), (7.19,2.97,7.41,3.19), (4.73,3.035,4.95,3.255), (0.35,3.16,0.57,3.38), (9.55,3.16,9.77,3.38)])
R(gf180mcu_fd_sc_mcu7t5v0_, metal1, [(1.475,1.785,3.27,2.12), (6.25,1.8,8.715,2.12)])
P(gf180mcu_fd_sc_mcu7t5v0_, metal1, [(0.825,1.585),(0.825,2.68),(3.82,2.68),(3.82,2.125),(4.48,2.125),(4.48,1.77),(3.5,1.77),(3.5,2.36),(1.165,2.36),(1.165,1.585)],
  [(6.01,0.99),(6.01,1.24),(4.755,1.24),(4.755,2.36),(4.11,2.36),(4.11,2.92),(2.175,2.92),(2.175,3.24),(4.385,3.24),(4.385,2.68),(5.195,2.68),(5.195,3.24),(7.865,3.24),(7.865,2.92),(5.445,2.92),(5.445,2.36),(5.015,2.36),(5.015,1.56),(8.59,1.56),(8.59,0.99),(8.25,0.99),(8.25,1.24),(6.35,1.24),(6.35,0.99)],
  [(8.955,1.585),(8.955,2.36),(6.02,2.36),(6.02,1.8),(5.27,1.8),(5.27,2.12),(5.69,2.12),(5.69,2.68),(9.295,2.68),(9.295,1.585)],
  [(0.19,0.53),(0.19,1.275),(4.455,1.275),(4.455,0.76),(9.94,0.76),(9.94,0.53),(4.225,0.53),(4.225,1.045),(2.77,1.045),(2.77,0.53),(2.43,0.53),(2.43,1.045),(0.53,1.045),(0.53,0.53)],
  [(0,-0.3),(0,0.3),(1.365,0.3),(1.365,0.815),(1.595,0.815),(1.595,0.3),(3.605,0.3),(3.605,0.815),(3.835,0.815),(3.835,0.3),(10.64,0.3),(10.64,-0.3)],
  [(0.345,2.59),(0.345,3.62),(0,3.62),(0,4.22),(10.64,4.22),(10.64,3.62),(9.775,3.62),(9.775,2.59),(9.545,2.59),(9.545,3.62),(4.955,3.62),(4.955,2.975),(4.725,2.975),(4.725,3.62),(0.575,3.62),(0.575,2.59)])
R(gf180mcu_fd_sc_mcu7t5v0_, dualgate, [(-0.28,-0.28,10.92,4.2)])
R(gf180mcu_fd_sc_mcu7t5v0_, v5_xtor, [(0,0,10.64,3.92)])
R(gf180mcu_fd_sc_mcu7t5v0_, lvpwell, [(-0.43,-0.43,11.07,1.76)])
gf180mcu_fd_sc_mcu7t5v0_.add(gdstk.Label('B2', (2.52,2.52), layer=34, texttype=10))
gf180mcu_fd_sc_mcu7t5v0_.add(gdstk.Label('VDD', (5.04,3.92), layer=34, texttype=10))
gf180mcu_fd_sc_mcu7t5v0_.add(gdstk.Label('VSS', (5.04,0), layer=34, texttype=10))
gf180mcu_fd_sc_mcu7t5v0_.add(gdstk.Label('ZN', (5.88,1.4), layer=34, texttype=10))
gf180mcu_fd_sc_mcu7t5v0_.add(gdstk.Label('A1', (7.56,1.96), layer=34, texttype=10))
gf180mcu_fd_sc_mcu7t5v0_.add(gdstk.Label('A2', (7,2.52), layer=34, texttype=10))
gf180mcu_fd_sc_mcu7t5v0_.add(gdstk.Label('B1', (2.52,1.96), layer=34, texttype=10))
gf180mcu_fd_sc_mcu7t5v0_.add(gdstk.Label('& Vendor GLOBALFOUNDRIES', (0,2), layer=63, texttype=63))
gf180mcu_fd_sc_mcu7t5v0_.add(gdstk.Label('& Product GF018hv5v_mcu_sc7', (0,1.5), layer=63, texttype=63))
gf180mcu_fd_sc_mcu7t5v0_.add(gdstk.Label('& Version 2015q2v1', (0,1), layer=63, texttype=63))
gf180mcu_fd_sc_mcu7t5v0_.add(gdstk.Label('& Metric 1.00', (0,0.5), layer=63, texttype=63))
gf180mcu_fd_sc_mcu7t5v0_.add(gdstk.Label('VNW', (0.345,3.92), layer=21, texttype=10))
gf180mcu_fd_sc_mcu7t5v0_.add(gdstk.Label('VPW', (0.34,-0.085), layer=204, texttype=10))

lib.write_gds('gf180mcu_fd_sc_mcu7t5v0__oai22_2.gds')
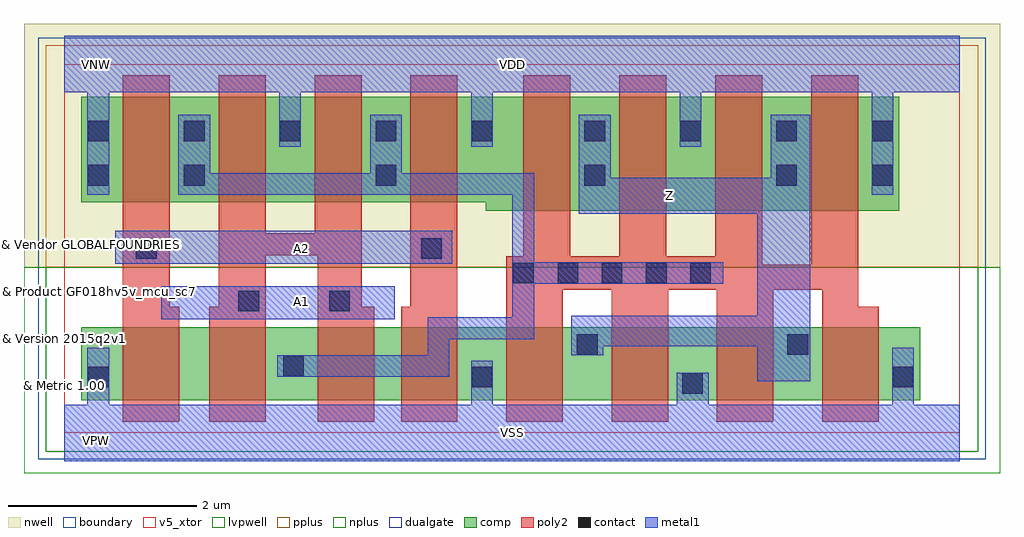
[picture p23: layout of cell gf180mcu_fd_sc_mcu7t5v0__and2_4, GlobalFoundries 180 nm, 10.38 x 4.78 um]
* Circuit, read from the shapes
.subckt gf180mcu_fd_sc_mcu7t5v0__and2_4 A1 A2 VDD VNW VSS Z
XM1 n1 A2 VSS VSUBS nfet_05v0 w=0.775u l=0.6u
XM2 n2 A1 n1 VSUBS nfet_05v0 w=0.775u l=0.6u
XM3 n3 A1 n2 VSUBS nfet_05v0 w=0.775u l=0.6u
XM4 VSS A2 n3 VSUBS nfet_05v0 w=0.775u l=0.6u
XM5 Z n2 VSS VSUBS nfet_05v0 w=0.775u l=0.6u m=4
XM6 n2 A2 VDD VNW pfet_05v0 w=1.125u l=0.5u m=2
XM7 VDD A1 n2 VNW pfet_05v0 w=1.125u l=0.5u m=2
XM8 Z n2 VDD VNW pfet_05v0 w=1.215u l=0.5u m=4
.ends

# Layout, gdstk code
import gdstk
lib = gdstk.Library(unit=1e-6, precision=1e-09)
def R(c, l, rs):  # rectangles x0, y0, x1, y1
    for r in rs: c.add(gdstk.rectangle(r[:2], r[2:], *l))
def A(c, l, x, y, w, h, nx, ny, dx, dy):  # array of equal rectangles
    R(c, l, [(x+i*dx, y+j*dy, x+i*dx+w, y+j*dy+h) for i in range(nx) for j in range(ny)])
def P(c, l, *ps):  # polygons
    for p in ps: c.add(gdstk.Polygon(p, *l))
boundary = (0, 0)
nwell = (21, 0)
comp = (22, 0)
poly2 = (30, 0)
pplus = (31, 0)
nplus = (32, 0)
contact = (33, 0)
metal1 = (34, 0)
dualgate = (55, 0)
v5_xtor = (112, 1)
lvpwell = (204, 0)

gf180mcu_fd_sc_mcu7t5v0_ = lib.new_cell('gf180mcu_fd_sc_mcu7t5v0__and2_4')
R(gf180mcu_fd_sc_mcu7t5v0_, boundary, [(0,0,9.52,3.92)])
R(gf180mcu_fd_sc_mcu7t5v0_, nwell, [(-0.43,1.76,9.95,4.35)])
R(gf180mcu_fd_sc_mcu7t5v0_, comp, [(0.18,0.345,9.1,1.12)])
P(gf180mcu_fd_sc_mcu7t5v0_, comp, [(4.48,2.36),(4.48,2.45),(0.18,2.45),(0.18,3.575),(8.88,3.575),(8.88,2.36)])
P(gf180mcu_fd_sc_mcu7t5v0_, poly2, [(0.62,0.12),(0.62,3.8),(1.12,3.8),(1.12,1.34),(1.22,1.34),(1.22,0.12)],
  [(1.54,0.12),(1.54,1.34),(1.64,1.34),(1.64,3.8),(2.14,3.8),(2.14,2.12),(2.66,2.12),(2.66,3.8),(3.16,3.8),(3.16,1.34),(3.295,1.34),(3.295,0.12),(2.695,0.12),(2.695,1.89),(2.14,1.89),(2.14,0.12)],
  [(3.58,0.12),(3.58,1.34),(3.68,1.34),(3.68,3.8),(4.18,3.8),(4.18,0.12)],
  [(4.7,0.12),(4.7,1.88),(4.88,1.88),(4.88,3.8),(5.38,3.8),(5.38,1.88),(5.9,1.88),(5.9,3.8),(6.4,3.8),(6.4,1.88),(6.92,1.88),(6.92,3.8),(7.42,3.8),(7.42,1.785),(7.94,1.785),(7.94,3.8),(8.44,3.8),(8.44,1.34),(8.66,1.34),(8.66,0.12),(8.06,0.12),(8.06,1.52),(7.54,1.52),(7.54,0.12),(6.94,0.12),(6.94,1.52),(6.42,1.52),(6.42,0.12),(5.82,0.12),(5.82,1.52),(5.3,1.52),(5.3,0.12)])
R(gf180mcu_fd_sc_mcu7t5v0_, pplus, [(-0.2,1.76,9.72,4.12)])
R(gf180mcu_fd_sc_mcu7t5v0_, nplus, [(-0.2,-0.2,9.72,1.76)])
A(gf180mcu_fd_sc_mcu7t5v0_, contact, 5.245, 1.59, 0.22, 0.22, 4, 1, 0.47, 0)
A(gf180mcu_fd_sc_mcu7t5v0_, contact, 0.25, 3.1, 0.22, 0.22, 5, 1, 1.02, 0)
A(gf180mcu_fd_sc_mcu7t5v0_, contact, 5.53, 3.1, 0.22, 0.22, 4, 1, 1.02, 0)
R(gf180mcu_fd_sc_mcu7t5v0_, contact, [(6.57,0.415,6.79,0.635), (0.25,0.485,0.47,0.705), (4.33,0.485,4.55,0.705), (8.81,0.485,9.03,0.705), (2.325,0.6,2.545,0.82), (5.45,0.83,5.67,1.05), (7.69,0.83,7.91,1.05), (1.85,1.29,2.07,1.51), (2.815,1.29,3.035,1.51), (4.77,1.59,4.99,1.81), (0.76,1.85,0.98,2.07), (3.795,1.85,4.015,2.07), (0.25,2.63,0.47,2.85), (1.27,2.63,1.49,2.85), (3.31,2.63,3.53,2.85), (5.53,2.63,5.75,2.85), (7.57,2.63,7.79,2.85), (8.59,2.63,8.81,2.85)])
R(gf180mcu_fd_sc_mcu7t5v0_, metal1, [(1.03,1.21,3.515,1.56), (0.54,1.8,4.125,2.15)])
P(gf180mcu_fd_sc_mcu7t5v0_, metal1, [(2.265,0.595),(2.265,0.825),(3.865,0.825),(3.865,1.23),(4.765,1.23),(4.765,2.53),(1.21,2.53),(1.21,3.38),(1.55,3.38),(1.55,2.76),(3.25,2.76),(3.25,3.38),(3.59,3.38),(3.59,2.76),(4.995,2.76),(4.995,1.815),(7.005,1.815),(7.005,1.585),(4.995,1.585),(4.995,0.995),(4.095,0.995),(4.095,0.595)],
  [(7.37,0.55),(7.37,0.92),(5.73,0.92),(5.73,0.825),(5.39,0.825),(5.39,1.245),(7.37,1.245),(7.37,2.33),(5.47,2.33),(5.47,3.38),(5.81,3.38),(5.81,2.71),(7.51,2.71),(7.51,3.38),(7.93,3.38),(7.93,0.55)],
  [(0,-0.3),(0,0.3),(0.245,0.3),(0.245,0.905),(0.475,0.905),(0.475,0.3),(4.325,0.3),(4.325,0.765),(4.555,0.765),(4.555,0.3),(6.51,0.3),(6.51,0.64),(6.85,0.64),(6.85,0.3),(8.805,0.3),(8.805,0.905),(9.035,0.905),(9.035,0.3),(9.52,0.3),(9.52,-0.3)],
  [(0.245,2.53),(0.245,3.62),(0,3.62),(0,4.22),(9.52,4.22),(9.52,3.62),(8.815,3.62),(8.815,2.53),(8.585,2.53),(8.585,3.62),(6.775,3.62),(6.775,3.04),(6.545,3.04),(6.545,3.62),(4.555,3.62),(4.555,3.04),(4.325,3.04),(4.325,3.62),(2.515,3.62),(2.515,3.04),(2.285,3.04),(2.285,3.62),(0.475,3.62),(0.475,2.53)])
R(gf180mcu_fd_sc_mcu7t5v0_, dualgate, [(-0.28,-0.28,9.8,4.2)])
R(gf180mcu_fd_sc_mcu7t5v0_, v5_xtor, [(0,0,9.52,3.92)])
R(gf180mcu_fd_sc_mcu7t5v0_, lvpwell, [(-0.43,-0.43,9.95,1.76)])
gf180mcu_fd_sc_mcu7t5v0_.add(gdstk.Label('A2', (2.52,1.96), layer=34, texttype=10))
gf180mcu_fd_sc_mcu7t5v0_.add(gdstk.Label('VDD', (4.76,3.92), layer=34, texttype=10))
gf180mcu_fd_sc_mcu7t5v0_.add(gdstk.Label('VSS', (4.76,0), layer=34, texttype=10))
gf180mcu_fd_sc_mcu7t5v0_.add(gdstk.Label('Z', (6.44,2.52), layer=34, texttype=10))
gf180mcu_fd_sc_mcu7t5v0_.add(gdstk.Label('A1', (2.52,1.4), layer=34, texttype=10))
gf180mcu_fd_sc_mcu7t5v0_.add(gdstk.Label('& Vendor GLOBALFOUNDRIES', (0,2), layer=63, texttype=63))
gf180mcu_fd_sc_mcu7t5v0_.add(gdstk.Label('& Product GF018hv5v_mcu_sc7', (0,1.5), layer=63, texttype=63))
gf180mcu_fd_sc_mcu7t5v0_.add(gdstk.Label('& Version 2015q2v1', (0,1), layer=63, texttype=63))
gf180mcu_fd_sc_mcu7t5v0_.add(gdstk.Label('& Metric 1.00', (0,0.5), layer=63, texttype=63))
gf180mcu_fd_sc_mcu7t5v0_.add(gdstk.Label('VNW', (0.345,3.92), layer=21, texttype=10))
gf180mcu_fd_sc_mcu7t5v0_.add(gdstk.Label('VPW', (0.34,-0.085), layer=204, texttype=10))

lib.write_gds('gf180mcu_fd_sc_mcu7t5v0__and2_4.gds')
